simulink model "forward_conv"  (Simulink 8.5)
settings: Solver=ode45  StartTime=0.0  StopTime=0.0005  FixedStep=1/40000  RelTol=1e-3

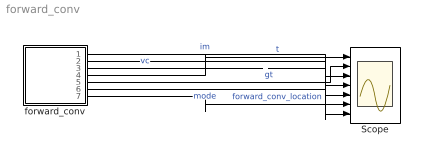
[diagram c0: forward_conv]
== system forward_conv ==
  Scope : Scope  NumInputPorts=7
  forward_conv : Stateflow chart  TreatAsAtomicUnit=on
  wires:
  forward_conv/4(t_out) -> Scope/1  "t"
  forward_conv/5(gt_out) -> Scope/2  "gt"
  forward_conv/3(vc_out) -> Scope/3  "vc"
  forward_conv/2(il_out) -> Scope/4  "il"
  forward_conv/1(im_out) -> Scope/5  "im"
  forward_conv/7(forward_conv_location) -> Scope/6  "forward_conv_location"
  forward_conv/6(mode_out) -> Scope/7  "mode"

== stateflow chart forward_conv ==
  state mode1
    du:
    im_dot = b1m1 * Vin;
    il_dot = a21m1 * im + a23m1 * vc + b2m1 * Vin;
    vc_dot = a32m1 * il + a33m1 * vc;
    t_dot = 1;
    gt_dot = 1;
    mode_dot = 0;
    im_out=im;
    il_out=il;
    vc_out=vc;
    t_out=t;
    gt_out=gt;
    mode_out=mode;
    forward_conv_location =1;
  state mode2
    du:
    im_dot = b1m2 * Vin;
    il_dot = a23m1 * vc;
    vc_dot = a32m1 * il + a33m1 * vc;
    t_dot = 1;
    gt_dot = 1;
    mode_dot = 0;
    im_out=im;
    il_out=il;
    vc_out=vc;
    t_out=t;
    gt_out=gt;
    mode_out=mode;
    forward_conv_location =2;
  state mode3
    du:
    im_dot = 0;
    il_dot = a23m1 * vc;
    vc_dot = a32m1 * il + a33m1 * vc;
    t_dot = 1;
    gt_dot = 1;
    mode_dot = 0;
    im_out=im;
    il_out=il;
    vc_out=vc;
    t_out=t;
    gt_out=gt;
    mode_out=mode;
    forward_conv_location =3;
  state mode4
    du:
    im_dot = 0;
    il_dot = 0;
    vc_dot = a33m1 * vc;
    t_dot = 1;
    gt_dot = 1;
    mode_dot = 0;
    im_out=im;
    il_out=il;
    vc_out=vc;
    t_out=t;
    gt_out=gt;
    mode_out=mode;
    forward_conv_location =4;
  state mode5
    du:
    im_dot = b1m2 * Vin;
    il_dot = 0;
    vc_dot = a33m1 * vc;
    t_dot = 1;
    gt_dot = 1;
    mode_dot = 0;
    im_out=im;
    il_out=il;
    vc_out=vc;
    t_out=t;
    gt_out=gt;
    mode_out=mode;
    forward_conv_location =5;
  mode4 -> mode1 : [t >= (1 - D) * T] {t = 0; gt = gt; vc = vc; il = il; im = im; mode = 1;}
  mode3 -> mode1 : [t >= (1 - D) * T] {t = 0; gt = gt; vc = vc; il = il; im = im; mode = 1;}
  mode1 -> mode2 : [t >= D * T] {t = 0; gt = gt; vc = vc; il = il; im = im; mode = 2;}
  mode2 -> mode3 : [im <= 0] {t = 0; gt = gt; vc = vc; il = il; im = im; mode = 3;}
  (default) -> mode1 : {im = 0; il = 0; vc = 0; t = 0; gt = 0; mode = 1;}
  mode5 -> mode4 : [im <= 0] {t = 0; gt = gt; vc = vc; il = il; im = im; mode = 4;}
  mode2 -> mode1 : [t >= (1 - D) * T] {t = 0; gt = gt; vc = vc; il = il; im = im; mode = 1;}
  mode2 -> mode5 : [il <= 0] {t = 0; gt = gt; vc = vc; il = il; im = im; mode = 5;}
  mode3 -> mode4 : [il <= 0] {t = 0; gt = gt; vc = vc; il = il; im = im; mode = 4;}
